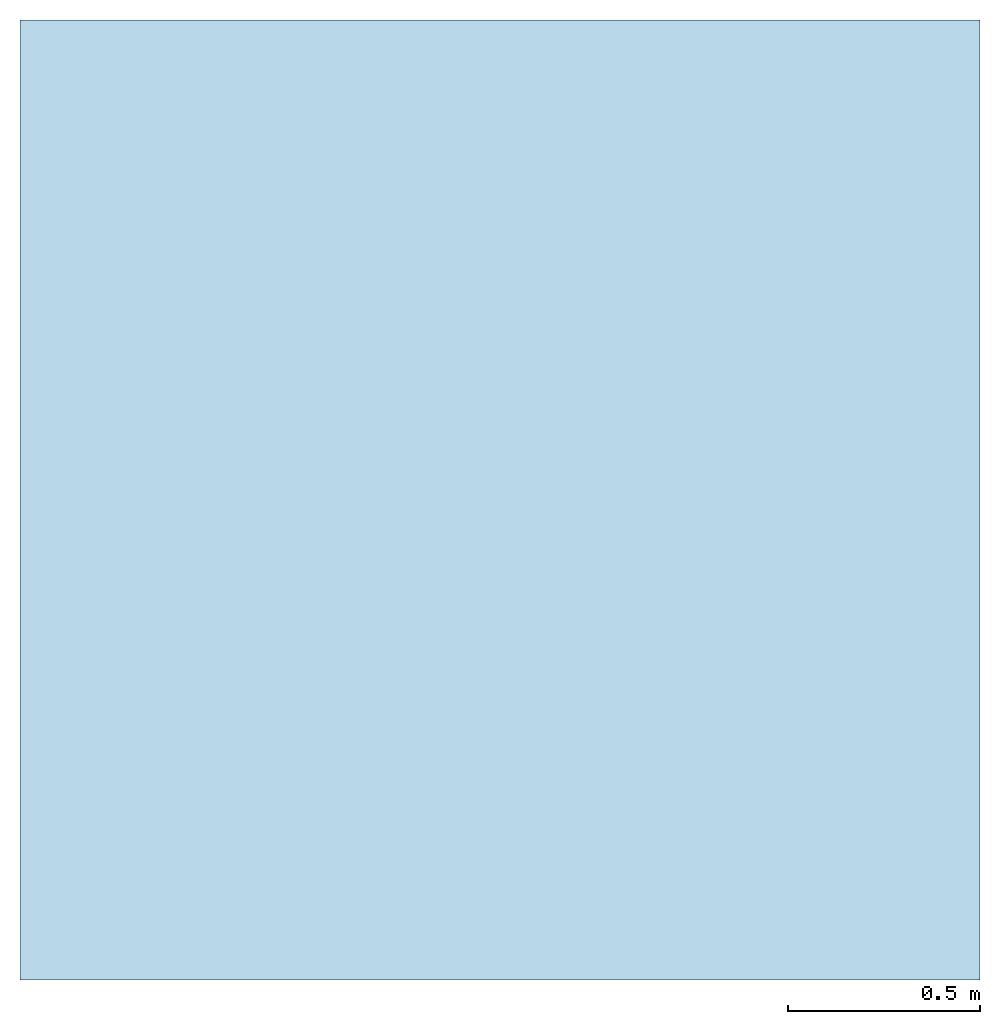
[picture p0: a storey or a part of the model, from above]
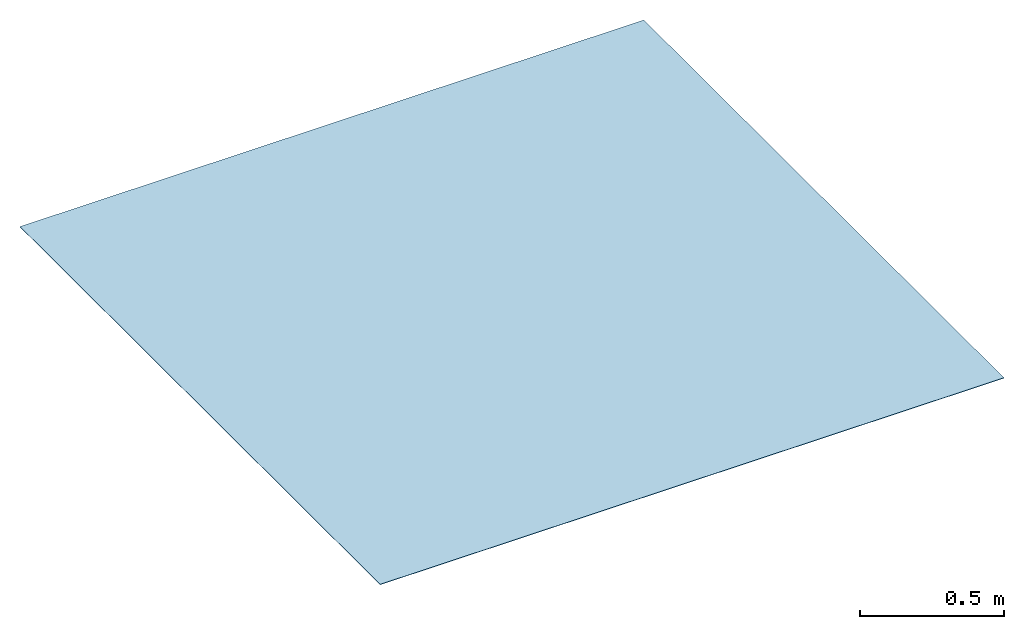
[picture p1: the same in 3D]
Properties of the parts of a building model (IFC2X3)

# File
Description: ViewDefinition[CoordinationView]
Time: 2018-01-30T09:29:22
Author: NBS
Written by: Xbim.Ifc File Processor version 2.4.1.0
Made in: Xbim version 2.4.1.0
Authorization: Add company name here

# IfcSlab: NBS_DeltaMembranes_CrysztnActvSlrryMtr_KosterNB1
In: Default building
Type - PredefinedType: FLOOR; Material: NBS_DeltaMembranes_CrysztnActvSlrryMtr_KosterNB1 2 mm
Type - xbim_MaterialFunctionAssignment - MaterialFunctionAssignment: 0: Substrate
Type - COBie - AccessibilityPerformance: n/a; AssetType: Fixed; Category: Pr_20_31_53_18:Crystallization active slurry mortars; CodePerformance: BS EN 1504-3; Color: Grey; Constituents: n/a; Description: Waterproofing against ground moisture, non-pressurized and pressurized water. New building and in the repair for horizontal and vertical waterproofing of concrete, masonry or cementitious plaster in wet rooms, bathrooms, showers, new-built basements, tanks, silos, sewage treatment plants, manholes, drinking water tanks, etc; DurationUnit: year; ExpectedLife: Life time of the building; Features: Mineral coating containing crystallizing and capillary-plugging agents, Excellent resistance to pressure, abrasion and chemicals, Highly effective waterproofing with bituminous building materials; Grade: n/a; Manufacturer: info@deltamembranes.com; ModelNumber: n/a; ModelReference: Koster NB1; Name: CrystallizationActiveSlurryMortar_KosterNB1_DeltaMembranes; NominalHeight: 0 mm; NominalLength: 1 mm; NominalWidth: 0 mm; ReplacementCost: n/a; Shape: n/a; Size: n/a; SustainabilityPerformance: n/a; WarrantyDescription: n/a; WarrantyDurationLabor: n/a; WarrantyDurationParts: 10; WarrantyDurationUnit: year; WarrantyGuarantorLabor: n/a; WarrantyGuarantorParts: info@deltamembranes.com
Type - Pset_CoveringCommon - AcousticRating: n/a; Combustible: yes; Finish: n/a; FireRating: Class E; FlammabilityRating: n/a; FragilityRating: n/a; Material: n/a; Reference: n/a; SurfaceSpreadOfFlame: n/a; TotalThickness: 1 mm
Type - NBS_Data - AdhesiveBond: ≥ 0.8 Mpa; ChlorideIonContent: ≤ 0.05 %; CompressiveStrength: Class R1; ElasticModulus: ≥10 Gpa; ThirdPartyProductCertification: European Technical Assessment ETA-17/0025
Type - NBS_General - Author: NBS; BIMObjectName: NBS_DeltaMembranes_CrystallizationActiveSlurryMortar_KosterNB1; ManufacturerName: Delta Membranes; ManufacturerURL: www.deltamembranes.com/; NBSCertification: www.nationalbimlibrary.com/cert/1xilj0nn; NBSDescription: Crystallization active slurry mortar; NBSNote: n/a; NBSOfficeMasterTag: n/a; NBSReference: 45-55-50/460; NBSTypeID: n/a; ProductInformation: www.deltamembranes.com/wp-content/uploads/KÖSTER-NB-1-Grey.pdf; Revision: n/a; Uniclass2015Code: Pr_20_31_53_18; Uniclass2015Title: Crystallization active slurry mortars; Uniclass2015Version: Products v1.8; Version: 1
Type - IFC - IfcExportAs: IfcCoveringType; IfcExportType: MEMBRANE
COBie - AssetIdentifier: n/a; BarCode: n/a; InstallationDate: 1900-12-31T23:59:59; SerialNumber: n/a; TagNumber: n/a; WarrantyStartDate: 1900-12-31T23:59:59
